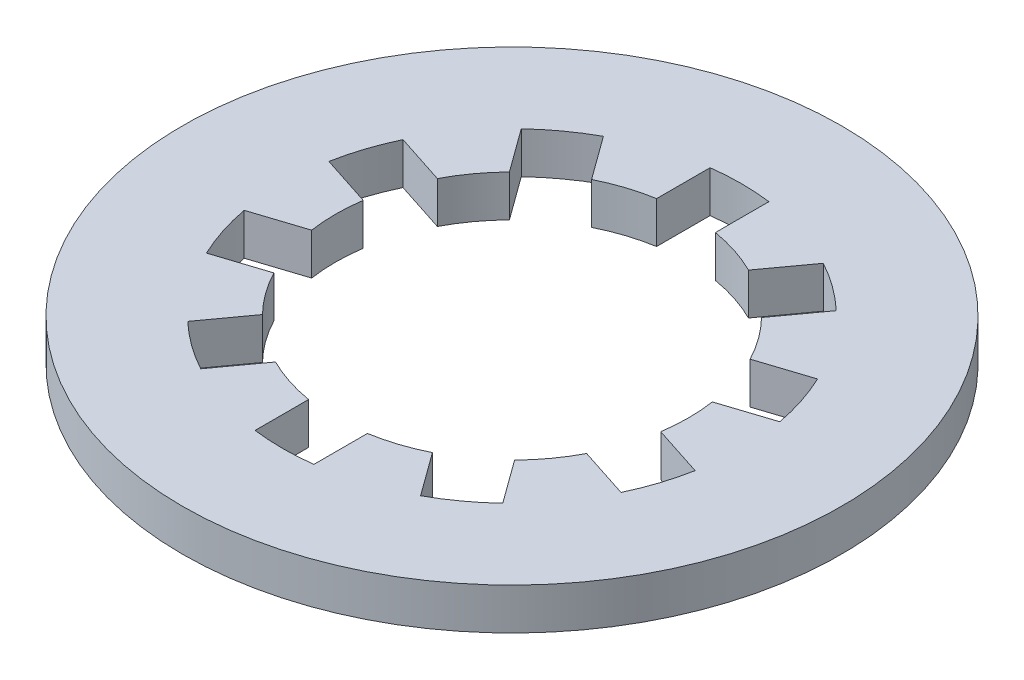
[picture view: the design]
ISO-10303-21;
HEADER;
FILE_DESCRIPTION(('STEP AP214'),'2;1');
FILE_NAME('part.step','',(''),(''),'','','');
FILE_SCHEMA(('AUTOMOTIVE_DESIGN { 1 0 10303 214 1 1 1 1 }'));
ENDSEC;
DATA;
#1=APPLICATION_CONTEXT('core data for automotive mechanical design processes');
#2=APPLICATION_PROTOCOL_DEFINITION('international standard','automotive_design',2000,#1);
#3=PRODUCT_CONTEXT('',#1,'mechanical');
#4=PRODUCT('Part','Part','',(#3));
#5=PRODUCT_RELATED_PRODUCT_CATEGORY('part','',(#4));
#6=PRODUCT_DEFINITION_FORMATION('','',#4);
#7=PRODUCT_DEFINITION_CONTEXT('part definition',#1,'design');
#8=PRODUCT_DEFINITION('design','',#6,#7);
#9=PRODUCT_DEFINITION_SHAPE('','',#8);
#10=(LENGTH_UNIT() NAMED_UNIT(*) SI_UNIT(.MILLI.,.METRE.));
#11=(NAMED_UNIT(*) PLANE_ANGLE_UNIT() SI_UNIT($,.RADIAN.));
#12=(NAMED_UNIT(*) SI_UNIT($,.STERADIAN.) SOLID_ANGLE_UNIT());
#13=UNCERTAINTY_MEASURE_WITH_UNIT(LENGTH_MEASURE(1.E-05),#10,'distance_accuracy_value','');
#14=(GEOMETRIC_REPRESENTATION_CONTEXT(3) GLOBAL_UNCERTAINTY_ASSIGNED_CONTEXT((#13)) GLOBAL_UNIT_ASSIGNED_CONTEXT((#10,
#11,#12)) REPRESENTATION_CONTEXT('',''));
#15=CARTESIAN_POINT('',(0.,0.,0.));
#16=DIRECTION('',(0.,0.,1.));
#17=DIRECTION('',(1.,0.,0.));
#18=AXIS2_PLACEMENT_3D('',#15,#16,#17);
#19=CARTESIAN_POINT('',(0.,0.6096,0.));
#20=DIRECTION('',(0.,-1.,0.));
#21=DIRECTION('',(0.,0.,-1.));
#22=AXIS2_PLACEMENT_3D('',#19,#20,#21);
#23=CYLINDRICAL_SURFACE('',#22,2.5908);
#24=DIRECTION('',(0.,1.,0.));
#25=VECTOR('',#24,1.);
#26=CARTESIAN_POINT('',(-1.15220106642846,0.,2.32049075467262));
#27=LINE('',#26,#25);
#28=CARTESIAN_POINT('',(-1.15220106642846,0.,2.32049075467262));
#29=VERTEX_POINT('',#28);
#30=CARTESIAN_POINT('',(-1.15220106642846,0.6096,2.32049075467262));
#31=VERTEX_POINT('',#30);
#32=EDGE_CURVE('E565',#29,#31,#27,.T.);
#33=ORIENTED_EDGE('',*,*,#32,.T.);
#34=CARTESIAN_POINT('',(0.,0.6096,0.));
#35=DIRECTION('',(0.,1.,0.));
#36=DIRECTION('',(0.,0.,1.));
#37=AXIS2_PLACEMENT_3D('',#34,#35,#36);
#38=CIRCLE('',#37,2.5908);
#39=CARTESIAN_POINT('',(-0.4318,0.6096,2.55456325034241));
#40=VERTEX_POINT('',#39);
#41=EDGE_CURVE('E332',#31,#40,#38,.T.);
#42=ORIENTED_EDGE('',*,*,#41,.T.);
#43=DIRECTION('',(0.,1.,0.));
#44=VECTOR('',#43,1.);
#45=CARTESIAN_POINT('',(-0.4318,0.,2.55456325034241));
#46=LINE('',#45,#44);
#47=CARTESIAN_POINT('',(-0.4318,0.,2.55456325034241));
#48=VERTEX_POINT('',#47);
#49=EDGE_CURVE('E340',#48,#40,#46,.T.);
#50=ORIENTED_EDGE('',*,*,#49,.F.);
#51=CARTESIAN_POINT('',(0.,0.,0.));
#52=DIRECTION('',(0.,1.,0.));
#53=DIRECTION('',(0.,0.,1.));
#54=AXIS2_PLACEMENT_3D('',#51,#52,#53);
#55=CIRCLE('',#54,2.5908);
#56=EDGE_CURVE('E322',#29,#48,#55,.T.);
#57=ORIENTED_EDGE('',*,*,#56,.F.);
#58=EDGE_LOOP('',(#33,#42,#50,#57));
#59=FACE_BOUND('',#58,.T.);
#60=ADVANCED_FACE('F41',(#59),#23,.F.);
#61=DIRECTION('',(0.,1.,0.));
#62=VECTOR('',#61,1.);
#63=CARTESIAN_POINT('',(-1.85086814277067,0.,1.81287941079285));
#64=LINE('',#63,#62);
#65=CARTESIAN_POINT('',(-1.85086814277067,0.,1.81287941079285));
#66=VERTEX_POINT('',#65);
#67=CARTESIAN_POINT('',(-1.85086814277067,0.6096,1.81287941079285));
#68=VERTEX_POINT('',#67);
#69=EDGE_CURVE('E301',#66,#68,#64,.T.);
#70=ORIENTED_EDGE('',*,*,#69,.F.);
#71=CARTESIAN_POINT('',(-2.29610048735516,0.,1.20006966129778));
#72=VERTEX_POINT('',#71);
#73=EDGE_CURVE('E312',#72,#66,#55,.T.);
#74=ORIENTED_EDGE('',*,*,#73,.F.);
#75=DIRECTION('',(0.,1.,0.));
#76=VECTOR('',#75,1.);
#77=CARTESIAN_POINT('',(-2.29610048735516,0.,1.20006966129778));
#78=LINE('',#77,#76);
#79=CARTESIAN_POINT('',(-2.29610048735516,0.6096,1.20006966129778));
#80=VERTEX_POINT('',#79);
#81=EDGE_CURVE('E537',#72,#80,#78,.T.);
#82=ORIENTED_EDGE('',*,*,#81,.T.);
#83=EDGE_CURVE('E314',#80,#68,#38,.T.);
#84=ORIENTED_EDGE('',*,*,#83,.T.);
#85=EDGE_LOOP('',(#70,#74,#82,#84));
#86=FACE_BOUND('',#85,.T.);
#87=ADVANCED_FACE('F311',(#86),#23,.F.);
#88=DIRECTION('',(0.,1.,0.));
#89=VECTOR('',#88,1.);
#90=CARTESIAN_POINT('',(-2.56296756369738,0.,0.378737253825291));
#91=LINE('',#90,#89);
#92=CARTESIAN_POINT('',(-2.56296756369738,0.,0.378737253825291));
#93=VERTEX_POINT('',#92);
#94=CARTESIAN_POINT('',(-2.56296756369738,0.6096,0.378737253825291));
#95=VERTEX_POINT('',#94);
#96=EDGE_CURVE('E547',#93,#95,#91,.T.);
#97=ORIENTED_EDGE('',*,*,#96,.F.);
#98=CARTESIAN_POINT('',(-2.56296756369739,0.,-0.378737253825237));
#99=VERTEX_POINT('',#98);
#100=EDGE_CURVE('E325',#99,#93,#55,.T.);
#101=ORIENTED_EDGE('',*,*,#100,.F.);
#102=DIRECTION('',(0.,1.,0.));
#103=VECTOR('',#102,1.);
#104=CARTESIAN_POINT('',(-2.56296756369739,0.,-0.378737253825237));
#105=LINE('',#104,#103);
#106=CARTESIAN_POINT('',(-2.56296756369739,0.6096,-0.378737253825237));
#107=VERTEX_POINT('',#106);
#108=EDGE_CURVE('E515',#99,#107,#105,.T.);
#109=ORIENTED_EDGE('',*,*,#108,.T.);
#110=EDGE_CURVE('E662',#107,#95,#38,.T.);
#111=ORIENTED_EDGE('',*,*,#110,.T.);
#112=EDGE_LOOP('',(#97,#101,#109,#111));
#113=FACE_BOUND('',#112,.T.);
#114=ADVANCED_FACE('F656',(#113),#23,.F.);
#115=DIRECTION('',(0.,1.,0.));
#116=VECTOR('',#115,1.);
#117=CARTESIAN_POINT('',(-2.29610048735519,0.,-1.20006966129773));
#118=LINE('',#117,#116);
#119=CARTESIAN_POINT('',(-2.29610048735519,0.,-1.20006966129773));
#120=VERTEX_POINT('',#119);
#121=CARTESIAN_POINT('',(-2.29610048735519,0.6096,-1.20006966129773));
#122=VERTEX_POINT('',#121);
#123=EDGE_CURVE('E519',#120,#122,#118,.T.);
#124=ORIENTED_EDGE('',*,*,#123,.F.);
#125=CARTESIAN_POINT('',(-1.85086814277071,0.,-1.81287941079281));
#126=VERTEX_POINT('',#125);
#127=EDGE_CURVE('E328',#126,#120,#55,.T.);
#128=ORIENTED_EDGE('',*,*,#127,.F.);
#129=DIRECTION('',(0.,1.,0.));
#130=VECTOR('',#129,1.);
#131=CARTESIAN_POINT('',(-1.85086814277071,0.,-1.81287941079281));
#132=LINE('',#131,#130);
#133=CARTESIAN_POINT('',(-1.85086814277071,0.6096,-1.81287941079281));
#134=VERTEX_POINT('',#133);
#135=EDGE_CURVE('E488',#126,#134,#132,.T.);
#136=ORIENTED_EDGE('',*,*,#135,.T.);
#137=EDGE_CURVE('E644',#134,#122,#38,.T.);
#138=ORIENTED_EDGE('',*,*,#137,.T.);
#139=EDGE_LOOP('',(#124,#128,#136,#138));
#140=FACE_BOUND('',#139,.T.);
#141=ADVANCED_FACE('F639',(#140),#23,.F.);
#142=DIRECTION('',(0.,1.,0.));
#143=VECTOR('',#142,1.);
#144=CARTESIAN_POINT('',(-1.15220106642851,0.,-2.3204907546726));
#145=LINE('',#144,#143);
#146=CARTESIAN_POINT('',(-1.15220106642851,0.,-2.3204907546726));
#147=VERTEX_POINT('',#146);
#148=CARTESIAN_POINT('',(-1.15220106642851,0.6096,-2.3204907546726));
#149=VERTEX_POINT('',#148);
#150=EDGE_CURVE('E494',#147,#149,#145,.T.);
#151=ORIENTED_EDGE('',*,*,#150,.F.);
#152=CARTESIAN_POINT('',(-0.431800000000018,0.,-2.55456325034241));
#153=VERTEX_POINT('',#152);
#154=EDGE_CURVE('E631',#153,#147,#55,.T.);
#155=ORIENTED_EDGE('',*,*,#154,.F.);
#156=DIRECTION('',(0.,1.,0.));
#157=VECTOR('',#156,1.);
#158=CARTESIAN_POINT('',(-0.431800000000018,0.,-2.55456325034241));
#159=LINE('',#158,#157);
#160=CARTESIAN_POINT('',(-0.431800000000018,0.6096,-2.55456325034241));
#161=VERTEX_POINT('',#160);
#162=EDGE_CURVE('E459',#153,#161,#159,.T.);
#163=ORIENTED_EDGE('',*,*,#162,.T.);
#164=EDGE_CURVE('E673',#161,#149,#38,.T.);
#165=ORIENTED_EDGE('',*,*,#164,.T.);
#166=EDGE_LOOP('',(#151,#155,#163,#165));
#167=FACE_BOUND('',#166,.T.);
#168=ADVANCED_FACE('F736',(#167),#23,.F.);
#169=DIRECTION('',(0.,1.,0.));
#170=VECTOR('',#169,1.);
#171=CARTESIAN_POINT('',(0.431799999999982,0.,-2.55456325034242));
#172=LINE('',#171,#170);
#173=CARTESIAN_POINT('',(0.431799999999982,0.,-2.55456325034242));
#174=VERTEX_POINT('',#173);
#175=CARTESIAN_POINT('',(0.431799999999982,0.6096,-2.55456325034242));
#176=VERTEX_POINT('',#175);
#177=EDGE_CURVE('E466',#174,#176,#172,.T.);
#178=ORIENTED_EDGE('',*,*,#177,.F.);
#179=CARTESIAN_POINT('',(1.15220106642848,0.,-2.32049075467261));
#180=VERTEX_POINT('',#179);
#181=EDGE_CURVE('E628',#180,#174,#55,.T.);
#182=ORIENTED_EDGE('',*,*,#181,.F.);
#183=DIRECTION('',(0.,1.,0.));
#184=VECTOR('',#183,1.);
#185=CARTESIAN_POINT('',(1.15220106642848,0.,-2.32049075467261));
#186=LINE('',#185,#184);
#187=CARTESIAN_POINT('',(1.15220106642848,0.6096,-2.32049075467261));
#188=VERTEX_POINT('',#187);
#189=EDGE_CURVE('E432',#180,#188,#186,.T.);
#190=ORIENTED_EDGE('',*,*,#189,.T.);
#191=EDGE_CURVE('E671',#188,#176,#38,.T.);
#192=ORIENTED_EDGE('',*,*,#191,.T.);
#193=EDGE_LOOP('',(#178,#182,#190,#192));
#194=FACE_BOUND('',#193,.T.);
#195=ADVANCED_FACE('F727',(#194),#23,.F.);
#196=DIRECTION('',(0.,1.,0.));
#197=VECTOR('',#196,1.);
#198=CARTESIAN_POINT('',(1.85086814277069,0.,-1.81287941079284));
#199=LINE('',#198,#197);
#200=CARTESIAN_POINT('',(1.85086814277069,0.,-1.81287941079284));
#201=VERTEX_POINT('',#200);
#202=CARTESIAN_POINT('',(1.85086814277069,0.6096,-1.81287941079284));
#203=VERTEX_POINT('',#202);
#204=EDGE_CURVE('E445',#201,#203,#199,.T.);
#205=ORIENTED_EDGE('',*,*,#204,.F.);
#206=CARTESIAN_POINT('',(2.29610048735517,0.,-1.20006966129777));
#207=VERTEX_POINT('',#206);
#208=EDGE_CURVE('E622',#207,#201,#55,.T.);
#209=ORIENTED_EDGE('',*,*,#208,.F.);
#210=DIRECTION('',(0.,1.,0.));
#211=VECTOR('',#210,1.);
#212=CARTESIAN_POINT('',(2.29610048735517,0.,-1.20006966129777));
#213=LINE('',#212,#211);
#214=CARTESIAN_POINT('',(2.29610048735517,0.6096,-1.20006966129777));
#215=VERTEX_POINT('',#214);
#216=EDGE_CURVE('E407',#207,#215,#213,.T.);
#217=ORIENTED_EDGE('',*,*,#216,.T.);
#218=EDGE_CURVE('E679',#215,#203,#38,.T.);
#219=ORIENTED_EDGE('',*,*,#218,.T.);
#220=EDGE_LOOP('',(#205,#209,#217,#219));
#221=FACE_BOUND('',#220,.T.);
#222=ADVANCED_FACE('F713',(#221),#23,.F.);
#223=DIRECTION('',(0.,1.,0.));
#224=VECTOR('',#223,1.);
#225=CARTESIAN_POINT('',(2.56296756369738,0.,-0.378737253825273));
#226=LINE('',#225,#224);
#227=CARTESIAN_POINT('',(2.56296756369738,0.,-0.378737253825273));
#228=VERTEX_POINT('',#227);
#229=CARTESIAN_POINT('',(2.56296756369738,0.6096,-0.378737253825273));
#230=VERTEX_POINT('',#229);
#231=EDGE_CURVE('E417',#228,#230,#226,.T.);
#232=ORIENTED_EDGE('',*,*,#231,.F.);
#233=CARTESIAN_POINT('',(2.56296756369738,0.,0.378737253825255));
#234=VERTEX_POINT('',#233);
#235=EDGE_CURVE('E621',#234,#228,#55,.T.);
#236=ORIENTED_EDGE('',*,*,#235,.F.);
#237=DIRECTION('',(0.,1.,0.));
#238=VECTOR('',#237,1.);
#239=CARTESIAN_POINT('',(2.56296756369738,0.,0.378737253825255));
#240=LINE('',#239,#238);
#241=CARTESIAN_POINT('',(2.56296756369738,0.6096,0.378737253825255));
#242=VERTEX_POINT('',#241);
#243=EDGE_CURVE('E385',#234,#242,#240,.T.);
#244=ORIENTED_EDGE('',*,*,#243,.T.);
#245=EDGE_CURVE('E681',#242,#230,#38,.T.);
#246=ORIENTED_EDGE('',*,*,#245,.T.);
#247=EDGE_LOOP('',(#232,#236,#244,#246));
#248=FACE_BOUND('',#247,.T.);
#249=ADVANCED_FACE('F705',(#248),#23,.F.);
#250=DIRECTION('',(0.,1.,0.));
#251=VECTOR('',#250,1.);
#252=CARTESIAN_POINT('',(2.29610048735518,0.,1.20006966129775));
#253=LINE('',#252,#251);
#254=CARTESIAN_POINT('',(2.29610048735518,0.,1.20006966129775));
#255=VERTEX_POINT('',#254);
#256=CARTESIAN_POINT('',(2.29610048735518,0.6096,1.20006966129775));
#257=VERTEX_POINT('',#256);
#258=EDGE_CURVE('E389',#255,#257,#253,.T.);
#259=ORIENTED_EDGE('',*,*,#258,.F.);
#260=CARTESIAN_POINT('',(1.8508681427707,0.,1.81287941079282));
#261=VERTEX_POINT('',#260);
#262=EDGE_CURVE('E335',#261,#255,#55,.T.);
#263=ORIENTED_EDGE('',*,*,#262,.F.);
#264=DIRECTION('',(0.,1.,0.));
#265=VECTOR('',#264,1.);
#266=CARTESIAN_POINT('',(1.8508681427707,0.,1.81287941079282));
#267=LINE('',#266,#265);
#268=CARTESIAN_POINT('',(1.8508681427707,0.6096,1.81287941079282));
#269=VERTEX_POINT('',#268);
#270=EDGE_CURVE('E358',#261,#269,#267,.T.);
#271=ORIENTED_EDGE('',*,*,#270,.T.);
#272=EDGE_CURVE('E337',#269,#257,#38,.T.);
#273=ORIENTED_EDGE('',*,*,#272,.T.);
#274=EDGE_LOOP('',(#259,#263,#271,#273));
#275=FACE_BOUND('',#274,.T.);
#276=ADVANCED_FACE('F623',(#275),#23,.F.);
#277=CARTESIAN_POINT('',(0.,0.6096,0.));
#278=DIRECTION('',(0.,1.,0.));
#279=DIRECTION('',(0.,0.,1.));
#280=AXIS2_PLACEMENT_3D('',#277,#278,#279);
#281=PLANE('',#280);
#282=DIRECTION('',(0.587785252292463,0.,-0.809016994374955));
#283=VECTOR('',#282,1.);
#284=CARTESIAN_POINT('',(-1.61401369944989,0.6096,2.95612131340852));
#285=LINE('',#284,#283);
#286=CARTESIAN_POINT('',(-1.61401369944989,0.6096,2.95612131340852));
#287=VERTEX_POINT('',#286);
#288=EDGE_CURVE('E306',#287,#31,#285,.T.);
#289=ORIENTED_EDGE('',*,*,#288,.F.);
#290=CARTESIAN_POINT('',(0.,0.6096,0.));
#291=DIRECTION('',(0.,1.,0.));
#292=DIRECTION('',(-0.587785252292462,0.,0.809016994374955));
#293=AXIS2_PLACEMENT_3D('',#290,#291,#292);
#294=CIRCLE('',#293,3.36804);
#295=CARTESIAN_POINT('',(-2.3126807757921,0.6096,2.44850996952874));
#296=VERTEX_POINT('',#295);
#297=EDGE_CURVE('E572',#296,#287,#294,.T.);
#298=ORIENTED_EDGE('',*,*,#297,.F.);
#299=DIRECTION('',(-0.587785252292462,0.,0.809016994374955));
#300=VECTOR('',#299,1.);
#301=CARTESIAN_POINT('',(-2.3126807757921,0.6096,2.44850996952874));
#302=LINE('',#301,#300);
#303=EDGE_CURVE('E577',#68,#296,#302,.T.);
#304=ORIENTED_EDGE('',*,*,#303,.F.);
#305=ORIENTED_EDGE('',*,*,#83,.F.);
#306=DIRECTION('',(0.95105651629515,0.,-0.309016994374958));
#307=VECTOR('',#306,1.);
#308=CARTESIAN_POINT('',(-3.04332902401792,0.6096,1.44285893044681));
#309=LINE('',#308,#307);
#310=CARTESIAN_POINT('',(-3.04332902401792,0.6096,1.44285893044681));
#311=VERTEX_POINT('',#310);
#312=EDGE_CURVE('E551',#311,#80,#309,.T.);
#313=ORIENTED_EDGE('',*,*,#312,.F.);
#314=CARTESIAN_POINT('',(0.,0.6096,0.));
#315=DIRECTION('',(0.,1.,0.));
#316=DIRECTION('',(-0.95105651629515,0.,0.309016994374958));
#317=AXIS2_PLACEMENT_3D('',#314,#315,#316);
#318=CIRCLE('',#317,3.36804);
#319=CARTESIAN_POINT('',(-3.31019610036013,0.6096,0.621526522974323));
#320=VERTEX_POINT('',#319);
#321=EDGE_CURVE('E558',#320,#311,#318,.T.);
#322=ORIENTED_EDGE('',*,*,#321,.F.);
#323=DIRECTION('',(-0.95105651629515,0.,0.309016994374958));
#324=VECTOR('',#323,1.);
#325=CARTESIAN_POINT('',(-3.31019610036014,0.6096,0.621526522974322));
#326=LINE('',#325,#324);
#327=EDGE_CURVE('E559',#95,#320,#326,.T.);
#328=ORIENTED_EDGE('',*,*,#327,.F.);
#329=ORIENTED_EDGE('',*,*,#110,.F.);
#330=DIRECTION('',(0.951056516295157,0.,0.309016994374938));
#331=VECTOR('',#330,1.);
#332=CARTESIAN_POINT('',(-3.31019610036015,0.6096,-0.621526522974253));
#333=LINE('',#332,#331);
#334=CARTESIAN_POINT('',(-3.31019610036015,0.6096,-0.621526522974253));
#335=VERTEX_POINT('',#334);
#336=EDGE_CURVE('E526',#335,#107,#333,.T.);
#337=ORIENTED_EDGE('',*,*,#336,.F.);
#338=CARTESIAN_POINT('',(0.,0.6096,0.));
#339=DIRECTION('',(0.,1.,0.));
#340=DIRECTION('',(-0.951056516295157,0.,-0.309016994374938));
#341=AXIS2_PLACEMENT_3D('',#338,#339,#340);
#342=CIRCLE('',#341,3.36804);
#343=CARTESIAN_POINT('',(-3.04332902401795,0.6096,-1.44285893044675));
#344=VERTEX_POINT('',#343);
#345=EDGE_CURVE('E535',#344,#335,#342,.T.);
#346=ORIENTED_EDGE('',*,*,#345,.F.);
#347=DIRECTION('',(-0.951056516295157,0.,-0.309016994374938));
#348=VECTOR('',#347,1.);
#349=CARTESIAN_POINT('',(-3.04332902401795,0.6096,-1.44285893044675));
#350=LINE('',#349,#348);
#351=EDGE_CURVE('E533',#122,#344,#350,.T.);
#352=ORIENTED_EDGE('',*,*,#351,.F.);
#353=ORIENTED_EDGE('',*,*,#137,.F.);
#354=DIRECTION('',(0.58778525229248,0.,0.809016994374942));
#355=VECTOR('',#354,1.);
#356=CARTESIAN_POINT('',(-2.31268077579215,0.6096,-2.44850996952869));
#357=LINE('',#356,#355);
#358=CARTESIAN_POINT('',(-2.31268077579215,0.6096,-2.44850996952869));
#359=VERTEX_POINT('',#358);
#360=EDGE_CURVE('E503',#359,#134,#357,.T.);
#361=ORIENTED_EDGE('',*,*,#360,.F.);
#362=CARTESIAN_POINT('',(0.,0.6096,0.));
#363=DIRECTION('',(0.,1.,0.));
#364=DIRECTION('',(-0.58778525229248,0.,-0.809016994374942));
#365=AXIS2_PLACEMENT_3D('',#362,#363,#364);
#366=CIRCLE('',#365,3.36804);
#367=CARTESIAN_POINT('',(-1.61401369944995,0.6096,-2.95612131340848));
#368=VERTEX_POINT('',#367);
#369=EDGE_CURVE('E506',#368,#359,#366,.T.);
#370=ORIENTED_EDGE('',*,*,#369,.F.);
#371=DIRECTION('',(-0.58778525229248,0.,-0.809016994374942));
#372=VECTOR('',#371,1.);
#373=CARTESIAN_POINT('',(-1.61401369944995,0.6096,-2.95612131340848));
#374=LINE('',#373,#372);
#375=EDGE_CURVE('E508',#149,#368,#374,.T.);
#376=ORIENTED_EDGE('',*,*,#375,.F.);
#377=ORIENTED_EDGE('',*,*,#164,.F.);
#378=DIRECTION('',(0.,0.,1.));
#379=VECTOR('',#378,1.);
#380=CARTESIAN_POINT('',(-0.431800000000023,0.6096,-3.34024582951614));
#381=LINE('',#380,#379);
#382=CARTESIAN_POINT('',(-0.431800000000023,0.6096,-3.34024582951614));
#383=VERTEX_POINT('',#382);
#384=EDGE_CURVE('E480',#383,#161,#381,.T.);
#385=ORIENTED_EDGE('',*,*,#384,.F.);
#386=CARTESIAN_POINT('',(0.,0.6096,0.));
#387=DIRECTION('',(0.,1.,0.));
#388=DIRECTION('',(0.,0.,-1.));
#389=AXIS2_PLACEMENT_3D('',#386,#387,#388);
#390=CIRCLE('',#389,3.36804);
#391=CARTESIAN_POINT('',(0.431799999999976,0.6096,-3.34024582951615));
#392=VERTEX_POINT('',#391);
#393=EDGE_CURVE('E479',#392,#383,#390,.T.);
#394=ORIENTED_EDGE('',*,*,#393,.F.);
#395=DIRECTION('',(0.,0.,-1.));
#396=VECTOR('',#395,1.);
#397=CARTESIAN_POINT('',(0.431799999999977,0.6096,-3.34024582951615));
#398=LINE('',#397,#396);
#399=EDGE_CURVE('E484',#176,#392,#398,.T.);
#400=ORIENTED_EDGE('',*,*,#399,.F.);
#401=ORIENTED_EDGE('',*,*,#191,.F.);
#402=DIRECTION('',(-0.587785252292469,0.,0.809016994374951));
#403=VECTOR('',#402,1.);
#404=CARTESIAN_POINT('',(1.61401369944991,0.6096,-2.9561213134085));
#405=LINE('',#404,#403);
#406=CARTESIAN_POINT('',(1.61401369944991,0.6096,-2.9561213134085));
#407=VERTEX_POINT('',#406);
#408=EDGE_CURVE('E451',#407,#188,#405,.T.);
#409=ORIENTED_EDGE('',*,*,#408,.F.);
#410=CARTESIAN_POINT('',(0.,0.6096,0.));
#411=DIRECTION('',(0.,1.,0.));
#412=DIRECTION('',(0.587785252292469,0.,-0.809016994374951));
#413=AXIS2_PLACEMENT_3D('',#410,#411,#412);
#414=CIRCLE('',#413,3.36804);
#415=CARTESIAN_POINT('',(2.31268077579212,0.6096,-2.44850996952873));
#416=VERTEX_POINT('',#415);
#417=EDGE_CURVE('E453',#416,#407,#414,.T.);
#418=ORIENTED_EDGE('',*,*,#417,.F.);
#419=DIRECTION('',(0.587785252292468,0.,-0.809016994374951));
#420=VECTOR('',#419,1.);
#421=CARTESIAN_POINT('',(2.31268077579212,0.6096,-2.44850996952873));
#422=LINE('',#421,#420);
#423=EDGE_CURVE('E460',#203,#416,#422,.T.);
#424=ORIENTED_EDGE('',*,*,#423,.F.);
#425=ORIENTED_EDGE('',*,*,#218,.F.);
#426=DIRECTION('',(-0.951056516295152,0.,0.309016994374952));
#427=VECTOR('',#426,1.);
#428=CARTESIAN_POINT('',(3.04332902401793,0.6096,-1.44285893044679));
#429=LINE('',#428,#427);
#430=CARTESIAN_POINT('',(3.04332902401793,0.6096,-1.44285893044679));
#431=VERTEX_POINT('',#430);
#432=EDGE_CURVE('E424',#431,#215,#429,.T.);
#433=ORIENTED_EDGE('',*,*,#432,.F.);
#434=CARTESIAN_POINT('',(0.,0.6096,0.));
#435=DIRECTION('',(0.,1.,0.));
#436=DIRECTION('',(0.951056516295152,0.,-0.309016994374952));
#437=AXIS2_PLACEMENT_3D('',#434,#435,#436);
#438=CIRCLE('',#437,3.36804);
#439=CARTESIAN_POINT('',(3.31019610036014,0.6096,-0.6215265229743));
#440=VERTEX_POINT('',#439);
#441=EDGE_CURVE('E426',#440,#431,#438,.T.);
#442=ORIENTED_EDGE('',*,*,#441,.F.);
#443=DIRECTION('',(0.951056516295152,0.,-0.309016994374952));
#444=VECTOR('',#443,1.);
#445=CARTESIAN_POINT('',(3.31019610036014,0.6096,-0.6215265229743));
#446=LINE('',#445,#444);
#447=EDGE_CURVE('E431',#230,#440,#446,.T.);
#448=ORIENTED_EDGE('',*,*,#447,.F.);
#449=ORIENTED_EDGE('',*,*,#245,.F.);
#450=DIRECTION('',(-0.951056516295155,0.,-0.309016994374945));
#451=VECTOR('',#450,1.);
#452=CARTESIAN_POINT('',(3.31019610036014,0.6096,0.621526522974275));
#453=LINE('',#452,#451);
#454=CARTESIAN_POINT('',(3.31019610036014,0.6096,0.621526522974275));
#455=VERTEX_POINT('',#454);
#456=EDGE_CURVE('E396',#455,#242,#453,.T.);
#457=ORIENTED_EDGE('',*,*,#456,.F.);
#458=CARTESIAN_POINT('',(0.,0.6096,0.));
#459=DIRECTION('',(0.,1.,0.));
#460=DIRECTION('',(0.951056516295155,0.,0.309016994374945));
#461=AXIS2_PLACEMENT_3D('',#458,#459,#460);
#462=CIRCLE('',#461,3.36804);
#463=CARTESIAN_POINT('',(3.04332902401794,0.6096,1.44285893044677));
#464=VERTEX_POINT('',#463);
#465=EDGE_CURVE('E405',#464,#455,#462,.T.);
#466=ORIENTED_EDGE('',*,*,#465,.F.);
#467=DIRECTION('',(0.951056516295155,0.,0.309016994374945));
#468=VECTOR('',#467,1.);
#469=CARTESIAN_POINT('',(3.04332902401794,0.6096,1.44285893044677));
#470=LINE('',#469,#468);
#471=EDGE_CURVE('E403',#257,#464,#470,.T.);
#472=ORIENTED_EDGE('',*,*,#471,.F.);
#473=ORIENTED_EDGE('',*,*,#272,.F.);
#474=DIRECTION('',(-0.587785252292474,0.,-0.809016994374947));
#475=VECTOR('',#474,1.);
#476=CARTESIAN_POINT('',(2.31268077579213,0.6096,2.44850996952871));
#477=LINE('',#476,#475);
#478=CARTESIAN_POINT('',(2.31268077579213,0.6096,2.44850996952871));
#479=VERTEX_POINT('',#478);
#480=EDGE_CURVE('E373',#479,#269,#477,.T.);
#481=ORIENTED_EDGE('',*,*,#480,.F.);
#482=CARTESIAN_POINT('',(0.,0.6096,0.));
#483=DIRECTION('',(0.,1.,0.));
#484=DIRECTION('',(0.587785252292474,0.,0.809016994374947));
#485=AXIS2_PLACEMENT_3D('',#482,#483,#484);
#486=CIRCLE('',#485,3.36804);
#487=CARTESIAN_POINT('',(1.61401369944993,0.6096,2.95612131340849));
#488=VERTEX_POINT('',#487);
#489=EDGE_CURVE('E376',#488,#479,#486,.T.);
#490=ORIENTED_EDGE('',*,*,#489,.F.);
#491=DIRECTION('',(0.587785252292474,0.,0.809016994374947));
#492=VECTOR('',#491,1.);
#493=CARTESIAN_POINT('',(1.61401369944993,0.6096,2.95612131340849));
#494=LINE('',#493,#492);
#495=CARTESIAN_POINT('',(1.1522010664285,0.6096,2.32049075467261));
#496=VERTEX_POINT('',#495);
#497=EDGE_CURVE('E378',#496,#488,#494,.T.);
#498=ORIENTED_EDGE('',*,*,#497,.F.);
#499=CARTESIAN_POINT('',(0.4318,0.6096,2.55456325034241));
#500=VERTEX_POINT('',#499);
#501=EDGE_CURVE('E334',#500,#496,#38,.T.);
#502=ORIENTED_EDGE('',*,*,#501,.F.);
#503=DIRECTION('',(0.,0.,-1.));
#504=VECTOR('',#503,1.);
#505=CARTESIAN_POINT('',(0.4318,0.6096,3.34024582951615));
#506=LINE('',#505,#504);
#507=CARTESIAN_POINT('',(0.4318,0.6096,3.34024582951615));
#508=VERTEX_POINT('',#507);
#509=EDGE_CURVE('E350',#508,#500,#506,.T.);
#510=ORIENTED_EDGE('',*,*,#509,.F.);
#511=CARTESIAN_POINT('',(0.,0.6096,0.));
#512=DIRECTION('',(0.,1.,0.));
#513=DIRECTION('',(0.,0.,1.));
#514=AXIS2_PLACEMENT_3D('',#511,#512,#513);
#515=CIRCLE('',#514,3.36804);
#516=CARTESIAN_POINT('',(-0.431799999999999,0.6096,3.34024582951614));
#517=VERTEX_POINT('',#516);
#518=EDGE_CURVE('E349',#517,#508,#515,.T.);
#519=ORIENTED_EDGE('',*,*,#518,.F.);
#520=DIRECTION('',(0.,0.,1.));
#521=VECTOR('',#520,1.);
#522=CARTESIAN_POINT('',(-0.4318,0.6096,3.34024582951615));
#523=LINE('',#522,#521);
#524=EDGE_CURVE('E354',#40,#517,#523,.T.);
#525=ORIENTED_EDGE('',*,*,#524,.F.);
#526=ORIENTED_EDGE('',*,*,#41,.F.);
#527=EDGE_LOOP('',(#289,#298,#304,#305,#313,#322,#328,#329,#337,#346,#352,#353,#361,#370,#376,
#377,#385,#394,#400,#401,#409,#418,#424,#425,#433,#442,#448,#449,#457,#466,#472,#473,#481,#490,
#498,#502,#510,#519,#525,#526));
#528=FACE_BOUND('',#527,.T.);
#529=CARTESIAN_POINT('',(0.,0.6096,0.));
#530=DIRECTION('',(0.,1.,0.));
#531=DIRECTION('',(0.,0.,1.));
#532=AXIS2_PLACEMENT_3D('',#529,#530,#531);
#533=CIRCLE('',#532,4.8387);
#534=CARTESIAN_POINT('',(0.,0.6096,4.8387));
#535=VERTEX_POINT('',#534);
#536=EDGE_CURVE('E11',#535,#535,#533,.T.);
#537=ORIENTED_EDGE('',*,*,#536,.T.);
#538=EDGE_LOOP('',(#537));
#539=FACE_BOUND('',#538,.T.);
#540=ADVANCED_FACE('F594',(#528,#539),#281,.T.);
#541=CARTESIAN_POINT('',(0.,0.,0.));
#542=DIRECTION('',(0.,1.,0.));
#543=DIRECTION('',(0.,0.,1.));
#544=AXIS2_PLACEMENT_3D('',#541,#542,#543);
#545=PLANE('',#544);
#546=CARTESIAN_POINT('',(0.,0.,0.));
#547=DIRECTION('',(0.,1.,0.));
#548=DIRECTION('',(0.,0.,1.));
#549=AXIS2_PLACEMENT_3D('',#546,#547,#548);
#550=CIRCLE('',#549,4.8387);
#551=CARTESIAN_POINT('',(0.,0.,4.8387));
#552=VERTEX_POINT('',#551);
#553=EDGE_CURVE('E44',#552,#552,#550,.T.);
#554=ORIENTED_EDGE('',*,*,#553,.F.);
#555=EDGE_LOOP('',(#554));
#556=FACE_BOUND('',#555,.T.);
#557=CARTESIAN_POINT('',(0.,0.,0.));
#558=DIRECTION('',(0.,1.,0.));
#559=DIRECTION('',(-0.587785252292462,0.,0.809016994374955));
#560=AXIS2_PLACEMENT_3D('',#557,#558,#559);
#561=CIRCLE('',#560,3.36804);
#562=CARTESIAN_POINT('',(-2.3126807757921,0.,2.44850996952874));
#563=VERTEX_POINT('',#562);
#564=CARTESIAN_POINT('',(-1.61401369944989,0.,2.95612131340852));
#565=VERTEX_POINT('',#564);
#566=EDGE_CURVE('E57',#563,#565,#561,.T.);
#567=ORIENTED_EDGE('',*,*,#566,.T.);
#568=DIRECTION('',(0.587785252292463,0.,-0.809016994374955));
#569=VECTOR('',#568,1.);
#570=CARTESIAN_POINT('',(-1.61401369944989,0.,2.95612131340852));
#571=LINE('',#570,#569);
#572=EDGE_CURVE('E317',#565,#29,#571,.T.);
#573=ORIENTED_EDGE('',*,*,#572,.T.);
#574=ORIENTED_EDGE('',*,*,#56,.T.);
#575=DIRECTION('',(0.,0.,1.));
#576=VECTOR('',#575,1.);
#577=CARTESIAN_POINT('',(-0.4318,0.,3.34024582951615));
#578=LINE('',#577,#576);
#579=CARTESIAN_POINT('',(-0.431799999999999,0.,3.34024582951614));
#580=VERTEX_POINT('',#579);
#581=EDGE_CURVE('E347',#48,#580,#578,.T.);
#582=ORIENTED_EDGE('',*,*,#581,.T.);
#583=CARTESIAN_POINT('',(0.,0.,0.));
#584=DIRECTION('',(0.,1.,0.));
#585=DIRECTION('',(0.,0.,1.));
#586=AXIS2_PLACEMENT_3D('',#583,#584,#585);
#587=CIRCLE('',#586,3.36804);
#588=CARTESIAN_POINT('',(0.4318,0.,3.34024582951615));
#589=VERTEX_POINT('',#588);
#590=EDGE_CURVE('E360',#580,#589,#587,.T.);
#591=ORIENTED_EDGE('',*,*,#590,.T.);
#592=DIRECTION('',(0.,0.,-1.));
#593=VECTOR('',#592,1.);
#594=CARTESIAN_POINT('',(0.4318,0.,3.34024582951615));
#595=LINE('',#594,#593);
#596=CARTESIAN_POINT('',(0.4318,0.,2.55456325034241));
#597=VERTEX_POINT('',#596);
#598=EDGE_CURVE('E341',#589,#597,#595,.T.);
#599=ORIENTED_EDGE('',*,*,#598,.T.);
#600=CARTESIAN_POINT('',(1.1522010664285,0.,2.3204907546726));
#601=VERTEX_POINT('',#600);
#602=EDGE_CURVE('E326',#597,#601,#55,.T.);
#603=ORIENTED_EDGE('',*,*,#602,.T.);
#604=DIRECTION('',(0.587785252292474,0.,0.809016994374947));
#605=VECTOR('',#604,1.);
#606=CARTESIAN_POINT('',(1.61401369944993,0.,2.95612131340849));
#607=LINE('',#606,#605);
#608=CARTESIAN_POINT('',(1.61401369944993,0.,2.95612131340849));
#609=VERTEX_POINT('',#608);
#610=EDGE_CURVE('E374',#601,#609,#607,.T.);
#611=ORIENTED_EDGE('',*,*,#610,.T.);
#612=CARTESIAN_POINT('',(0.,0.,0.));
#613=DIRECTION('',(0.,1.,0.));
#614=DIRECTION('',(0.587785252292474,0.,0.809016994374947));
#615=AXIS2_PLACEMENT_3D('',#612,#613,#614);
#616=CIRCLE('',#615,3.36804);
#617=CARTESIAN_POINT('',(2.31268077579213,0.,2.44850996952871));
#618=VERTEX_POINT('',#617);
#619=EDGE_CURVE('E383',#609,#618,#616,.T.);
#620=ORIENTED_EDGE('',*,*,#619,.T.);
#621=DIRECTION('',(-0.587785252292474,0.,-0.809016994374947));
#622=VECTOR('',#621,1.);
#623=CARTESIAN_POINT('',(2.31268077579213,0.,2.44850996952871));
#624=LINE('',#623,#622);
#625=EDGE_CURVE('E370',#618,#261,#624,.T.);
#626=ORIENTED_EDGE('',*,*,#625,.T.);
#627=ORIENTED_EDGE('',*,*,#262,.T.);
#628=DIRECTION('',(0.951056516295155,0.,0.309016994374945));
#629=VECTOR('',#628,1.);
#630=CARTESIAN_POINT('',(3.04332902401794,0.,1.44285893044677));
#631=LINE('',#630,#629);
#632=CARTESIAN_POINT('',(3.04332902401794,0.,1.44285893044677));
#633=VERTEX_POINT('',#632);
#634=EDGE_CURVE('E402',#255,#633,#631,.T.);
#635=ORIENTED_EDGE('',*,*,#634,.T.);
#636=CARTESIAN_POINT('',(0.,0.,0.));
#637=DIRECTION('',(0.,1.,0.));
#638=DIRECTION('',(0.951056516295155,0.,0.309016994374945));
#639=AXIS2_PLACEMENT_3D('',#636,#637,#638);
#640=CIRCLE('',#639,3.36804);
#641=CARTESIAN_POINT('',(3.31019610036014,0.,0.621526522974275));
#642=VERTEX_POINT('',#641);
#643=EDGE_CURVE('E413',#633,#642,#640,.T.);
#644=ORIENTED_EDGE('',*,*,#643,.T.);
#645=DIRECTION('',(-0.951056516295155,0.,-0.309016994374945));
#646=VECTOR('',#645,1.);
#647=CARTESIAN_POINT('',(3.31019610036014,0.,0.621526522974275));
#648=LINE('',#647,#646);
#649=EDGE_CURVE('E391',#642,#234,#648,.T.);
#650=ORIENTED_EDGE('',*,*,#649,.T.);
#651=ORIENTED_EDGE('',*,*,#235,.T.);
#652=DIRECTION('',(0.951056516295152,0.,-0.309016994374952));
#653=VECTOR('',#652,1.);
#654=CARTESIAN_POINT('',(3.31019610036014,0.,-0.6215265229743));
#655=LINE('',#654,#653);
#656=CARTESIAN_POINT('',(3.31019610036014,0.,-0.621526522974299));
#657=VERTEX_POINT('',#656);
#658=EDGE_CURVE('E430',#228,#657,#655,.T.);
#659=ORIENTED_EDGE('',*,*,#658,.T.);
#660=CARTESIAN_POINT('',(0.,0.,0.));
#661=DIRECTION('',(0.,1.,0.));
#662=DIRECTION('',(0.951056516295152,0.,-0.309016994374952));
#663=AXIS2_PLACEMENT_3D('',#660,#661,#662);
#664=CIRCLE('',#663,3.36804);
#665=CARTESIAN_POINT('',(3.04332902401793,0.,-1.44285893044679));
#666=VERTEX_POINT('',#665);
#667=EDGE_CURVE('E440',#657,#666,#664,.T.);
#668=ORIENTED_EDGE('',*,*,#667,.T.);
#669=DIRECTION('',(-0.951056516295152,0.,0.309016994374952));
#670=VECTOR('',#669,1.);
#671=CARTESIAN_POINT('',(3.04332902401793,0.,-1.44285893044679));
#672=LINE('',#671,#670);
#673=EDGE_CURVE('E416',#666,#207,#672,.T.);
#674=ORIENTED_EDGE('',*,*,#673,.T.);
#675=ORIENTED_EDGE('',*,*,#208,.T.);
#676=DIRECTION('',(0.587785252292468,0.,-0.809016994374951));
#677=VECTOR('',#676,1.);
#678=CARTESIAN_POINT('',(2.31268077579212,0.,-2.44850996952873));
#679=LINE('',#678,#677);
#680=CARTESIAN_POINT('',(2.31268077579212,0.,-2.44850996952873));
#681=VERTEX_POINT('',#680);
#682=EDGE_CURVE('E452',#201,#681,#679,.T.);
#683=ORIENTED_EDGE('',*,*,#682,.T.);
#684=CARTESIAN_POINT('',(0.,0.,0.));
#685=DIRECTION('',(0.,1.,0.));
#686=DIRECTION('',(0.587785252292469,0.,-0.809016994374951));
#687=AXIS2_PLACEMENT_3D('',#684,#685,#686);
#688=CIRCLE('',#687,3.36804);
#689=CARTESIAN_POINT('',(1.61401369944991,0.,-2.9561213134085));
#690=VERTEX_POINT('',#689);
#691=EDGE_CURVE('E464',#681,#690,#688,.T.);
#692=ORIENTED_EDGE('',*,*,#691,.T.);
#693=DIRECTION('',(-0.587785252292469,0.,0.809016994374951));
#694=VECTOR('',#693,1.);
#695=CARTESIAN_POINT('',(1.61401369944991,0.,-2.9561213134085));
#696=LINE('',#695,#694);
#697=EDGE_CURVE('E444',#690,#180,#696,.T.);
#698=ORIENTED_EDGE('',*,*,#697,.T.);
#699=ORIENTED_EDGE('',*,*,#181,.T.);
#700=DIRECTION('',(0.,0.,-1.));
#701=VECTOR('',#700,1.);
#702=CARTESIAN_POINT('',(0.431799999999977,0.,-3.34024582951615));
#703=LINE('',#702,#701);
#704=CARTESIAN_POINT('',(0.431799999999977,0.,-3.34024582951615));
#705=VERTEX_POINT('',#704);
#706=EDGE_CURVE('E477',#174,#705,#703,.T.);
#707=ORIENTED_EDGE('',*,*,#706,.T.);
#708=CARTESIAN_POINT('',(0.,0.,0.));
#709=DIRECTION('',(0.,1.,0.));
#710=DIRECTION('',(0.,0.,-1.));
#711=AXIS2_PLACEMENT_3D('',#708,#709,#710);
#712=CIRCLE('',#711,3.36804);
#713=CARTESIAN_POINT('',(-0.431800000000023,0.,-3.34024582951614));
#714=VERTEX_POINT('',#713);
#715=EDGE_CURVE('E490',#705,#714,#712,.T.);
#716=ORIENTED_EDGE('',*,*,#715,.T.);
#717=DIRECTION('',(0.,0.,1.));
#718=VECTOR('',#717,1.);
#719=CARTESIAN_POINT('',(-0.431800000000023,0.,-3.34024582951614));
#720=LINE('',#719,#718);
#721=EDGE_CURVE('E471',#714,#153,#720,.T.);
#722=ORIENTED_EDGE('',*,*,#721,.T.);
#723=ORIENTED_EDGE('',*,*,#154,.T.);
#724=DIRECTION('',(-0.58778525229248,0.,-0.809016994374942));
#725=VECTOR('',#724,1.);
#726=CARTESIAN_POINT('',(-1.61401369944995,0.,-2.95612131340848));
#727=LINE('',#726,#725);
#728=CARTESIAN_POINT('',(-1.61401369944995,0.,-2.95612131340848));
#729=VERTEX_POINT('',#728);
#730=EDGE_CURVE('E504',#147,#729,#727,.T.);
#731=ORIENTED_EDGE('',*,*,#730,.T.);
#732=CARTESIAN_POINT('',(0.,0.,0.));
#733=DIRECTION('',(0.,1.,0.));
#734=DIRECTION('',(-0.58778525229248,0.,-0.809016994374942));
#735=AXIS2_PLACEMENT_3D('',#732,#733,#734);
#736=CIRCLE('',#735,3.36804);
#737=CARTESIAN_POINT('',(-2.31268077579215,0.,-2.44850996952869));
#738=VERTEX_POINT('',#737);
#739=EDGE_CURVE('E513',#729,#738,#736,.T.);
#740=ORIENTED_EDGE('',*,*,#739,.T.);
#741=DIRECTION('',(0.58778525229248,0.,0.809016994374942));
#742=VECTOR('',#741,1.);
#743=CARTESIAN_POINT('',(-2.31268077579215,0.,-2.44850996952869));
#744=LINE('',#743,#742);
#745=EDGE_CURVE('E500',#738,#126,#744,.T.);
#746=ORIENTED_EDGE('',*,*,#745,.T.);
#747=ORIENTED_EDGE('',*,*,#127,.T.);
#748=DIRECTION('',(-0.951056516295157,0.,-0.309016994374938));
#749=VECTOR('',#748,1.);
#750=CARTESIAN_POINT('',(-3.04332902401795,0.,-1.44285893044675));
#751=LINE('',#750,#749);
#752=CARTESIAN_POINT('',(-3.04332902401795,0.,-1.44285893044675));
#753=VERTEX_POINT('',#752);
#754=EDGE_CURVE('E532',#120,#753,#751,.T.);
#755=ORIENTED_EDGE('',*,*,#754,.T.);
#756=CARTESIAN_POINT('',(0.,0.,0.));
#757=DIRECTION('',(0.,1.,0.));
#758=DIRECTION('',(-0.951056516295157,0.,-0.309016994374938));
#759=AXIS2_PLACEMENT_3D('',#756,#757,#758);
#760=CIRCLE('',#759,3.36804);
#761=CARTESIAN_POINT('',(-3.31019610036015,0.,-0.621526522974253));
#762=VERTEX_POINT('',#761);
#763=EDGE_CURVE('E543',#753,#762,#760,.T.);
#764=ORIENTED_EDGE('',*,*,#763,.T.);
#765=DIRECTION('',(0.951056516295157,0.,0.309016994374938));
#766=VECTOR('',#765,1.);
#767=CARTESIAN_POINT('',(-3.31019610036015,0.,-0.621526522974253));
#768=LINE('',#767,#766);
#769=EDGE_CURVE('E521',#762,#99,#768,.T.);
#770=ORIENTED_EDGE('',*,*,#769,.T.);
#771=ORIENTED_EDGE('',*,*,#100,.T.);
#772=DIRECTION('',(-0.95105651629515,0.,0.309016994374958));
#773=VECTOR('',#772,1.);
#774=CARTESIAN_POINT('',(-3.31019610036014,0.,0.621526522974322));
#775=LINE('',#774,#773);
#776=CARTESIAN_POINT('',(-3.31019610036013,0.,0.621526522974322));
#777=VERTEX_POINT('',#776);
#778=EDGE_CURVE('E554',#93,#777,#775,.T.);
#779=ORIENTED_EDGE('',*,*,#778,.T.);
#780=CARTESIAN_POINT('',(0.,0.,0.));
#781=DIRECTION('',(0.,1.,0.));
#782=DIRECTION('',(-0.95105651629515,0.,0.309016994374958));
#783=AXIS2_PLACEMENT_3D('',#780,#781,#782);
#784=CIRCLE('',#783,3.36804);
#785=CARTESIAN_POINT('',(-3.04332902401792,0.,1.44285893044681));
#786=VERTEX_POINT('',#785);
#787=EDGE_CURVE('E63',#777,#786,#784,.T.);
#788=ORIENTED_EDGE('',*,*,#787,.T.);
#789=DIRECTION('',(0.95105651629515,0.,-0.309016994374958));
#790=VECTOR('',#789,1.);
#791=CARTESIAN_POINT('',(-3.04332902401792,0.,1.44285893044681));
#792=LINE('',#791,#790);
#793=EDGE_CURVE('E321',#786,#72,#792,.T.);
#794=ORIENTED_EDGE('',*,*,#793,.T.);
#795=ORIENTED_EDGE('',*,*,#73,.T.);
#796=DIRECTION('',(-0.587785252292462,0.,0.809016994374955));
#797=VECTOR('',#796,1.);
#798=CARTESIAN_POINT('',(-2.3126807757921,0.,2.44850996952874));
#799=LINE('',#798,#797);
#800=EDGE_CURVE('E300',#66,#563,#799,.T.);
#801=ORIENTED_EDGE('',*,*,#800,.T.);
#802=EDGE_LOOP('',(#567,#573,#574,#582,#591,#599,#603,#611,#620,#626,#627,#635,#644,#650,#651,
#659,#668,#674,#675,#683,#692,#698,#699,#707,#716,#722,#723,#731,#740,#746,#747,#755,#764,#770,
#771,#779,#788,#794,#795,#801));
#803=FACE_BOUND('',#802,.T.);
#804=ADVANCED_FACE('F316',(#556,#803),#545,.F.);
#805=CARTESIAN_POINT('',(0.,0.6096,0.));
#806=DIRECTION('',(0.,-1.,0.));
#807=DIRECTION('',(0.,0.,-1.));
#808=AXIS2_PLACEMENT_3D('',#805,#806,#807);
#809=CYLINDRICAL_SURFACE('',#808,4.8387);
#810=ORIENTED_EDGE('',*,*,#536,.F.);
#811=EDGE_LOOP('',(#810));
#812=FACE_BOUND('',#811,.T.);
#813=ORIENTED_EDGE('',*,*,#553,.T.);
#814=EDGE_LOOP('',(#813));
#815=FACE_BOUND('',#814,.T.);
#816=ADVANCED_FACE('F43',(#812,#815),#809,.T.);
#817=DIRECTION('',(0.,1.,0.));
#818=VECTOR('',#817,1.);
#819=CARTESIAN_POINT('',(1.1522010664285,0.,2.32049075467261));
#820=LINE('',#819,#818);
#821=EDGE_CURVE('E364',#601,#496,#820,.T.);
#822=ORIENTED_EDGE('',*,*,#821,.F.);
#823=ORIENTED_EDGE('',*,*,#602,.F.);
#824=DIRECTION('',(0.,1.,0.));
#825=VECTOR('',#824,1.);
#826=CARTESIAN_POINT('',(0.4318,0.,2.55456325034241));
#827=LINE('',#826,#825);
#828=EDGE_CURVE('E330',#597,#500,#827,.T.);
#829=ORIENTED_EDGE('',*,*,#828,.T.);
#830=ORIENTED_EDGE('',*,*,#501,.T.);
#831=EDGE_LOOP('',(#822,#823,#829,#830));
#832=FACE_BOUND('',#831,.T.);
#833=ADVANCED_FACE('F604',(#832),#23,.F.);
#834=CARTESIAN_POINT('',(0.4318,0.,3.34024582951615));
#835=DIRECTION('',(1.,0.,0.));
#836=DIRECTION('',(0.,0.,-1.));
#837=AXIS2_PLACEMENT_3D('',#834,#835,#836);
#838=PLANE('',#837);
#839=ORIENTED_EDGE('',*,*,#509,.T.);
#840=ORIENTED_EDGE('',*,*,#828,.F.);
#841=ORIENTED_EDGE('',*,*,#598,.F.);
#842=DIRECTION('',(0.,1.,0.));
#843=VECTOR('',#842,1.);
#844=CARTESIAN_POINT('',(0.4318,0.,3.34024582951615));
#845=LINE('',#844,#843);
#846=EDGE_CURVE('E342',#589,#508,#845,.T.);
#847=ORIENTED_EDGE('',*,*,#846,.T.);
#848=EDGE_LOOP('',(#839,#840,#841,#847));
#849=FACE_BOUND('',#848,.T.);
#850=ADVANCED_FACE('F767',(#849),#838,.F.);
#851=CARTESIAN_POINT('',(0.,0.,0.));
#852=DIRECTION('',(0.,1.,0.));
#853=DIRECTION('',(0.,0.,1.));
#854=AXIS2_PLACEMENT_3D('',#851,#852,#853);
#855=CYLINDRICAL_SURFACE('',#854,3.36804);
#856=ORIENTED_EDGE('',*,*,#518,.T.);
#857=ORIENTED_EDGE('',*,*,#846,.F.);
#858=ORIENTED_EDGE('',*,*,#590,.F.);
#859=DIRECTION('',(0.,1.,0.));
#860=VECTOR('',#859,1.);
#861=CARTESIAN_POINT('',(-0.431799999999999,0.,3.34024582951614));
#862=LINE('',#861,#860);
#863=EDGE_CURVE('E338',#580,#517,#862,.T.);
#864=ORIENTED_EDGE('',*,*,#863,.T.);
#865=EDGE_LOOP('',(#856,#857,#858,#864));
#866=FACE_BOUND('',#865,.T.);
#867=ADVANCED_FACE('F596',(#866),#855,.F.);
#868=CARTESIAN_POINT('',(-0.4318,0.,3.34024582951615));
#869=DIRECTION('',(-1.,0.,0.));
#870=DIRECTION('',(0.,0.,1.));
#871=AXIS2_PLACEMENT_3D('',#868,#869,#870);
#872=PLANE('',#871);
#873=ORIENTED_EDGE('',*,*,#524,.T.);
#874=ORIENTED_EDGE('',*,*,#863,.F.);
#875=ORIENTED_EDGE('',*,*,#581,.F.);
#876=ORIENTED_EDGE('',*,*,#49,.T.);
#877=EDGE_LOOP('',(#873,#874,#875,#876));
#878=FACE_BOUND('',#877,.T.);
#879=ADVANCED_FACE('F587',(#878),#872,.F.);
#880=CARTESIAN_POINT('',(2.31268077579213,0.,2.44850996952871));
#881=DIRECTION('',(0.809016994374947,0.,-0.587785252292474));
#882=DIRECTION('',(-0.587785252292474,0.,-0.809016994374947));
#883=AXIS2_PLACEMENT_3D('',#880,#881,#882);
#884=PLANE('',#883);
#885=ORIENTED_EDGE('',*,*,#480,.T.);
#886=ORIENTED_EDGE('',*,*,#270,.F.);
#887=ORIENTED_EDGE('',*,*,#625,.F.);
#888=DIRECTION('',(0.,1.,0.));
#889=VECTOR('',#888,1.);
#890=CARTESIAN_POINT('',(2.31268077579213,0.,2.44850996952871));
#891=LINE('',#890,#889);
#892=EDGE_CURVE('E367',#618,#479,#891,.T.);
#893=ORIENTED_EDGE('',*,*,#892,.T.);
#894=EDGE_LOOP('',(#885,#886,#887,#893));
#895=FACE_BOUND('',#894,.T.);
#896=ADVANCED_FACE('F818',(#895),#884,.F.);
#897=CARTESIAN_POINT('',(0.,0.,0.));
#898=DIRECTION('',(0.,1.,0.));
#899=DIRECTION('',(0.,0.,1.));
#900=AXIS2_PLACEMENT_3D('',#897,#898,#899);
#901=CYLINDRICAL_SURFACE('',#900,3.36804);
#902=ORIENTED_EDGE('',*,*,#489,.T.);
#903=ORIENTED_EDGE('',*,*,#892,.F.);
#904=ORIENTED_EDGE('',*,*,#619,.F.);
#905=DIRECTION('',(0.,1.,0.));
#906=VECTOR('',#905,1.);
#907=CARTESIAN_POINT('',(1.61401369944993,0.,2.95612131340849));
#908=LINE('',#907,#906);
#909=EDGE_CURVE('E366',#609,#488,#908,.T.);
#910=ORIENTED_EDGE('',*,*,#909,.T.);
#911=EDGE_LOOP('',(#902,#903,#904,#910));
#912=FACE_BOUND('',#911,.T.);
#913=ADVANCED_FACE('F614',(#912),#901,.F.);
#914=CARTESIAN_POINT('',(1.61401369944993,0.,2.95612131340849));
#915=DIRECTION('',(-0.809016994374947,0.,0.587785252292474));
#916=DIRECTION('',(0.587785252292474,0.,0.809016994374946));
#917=AXIS2_PLACEMENT_3D('',#914,#915,#916);
#918=PLANE('',#917);
#919=ORIENTED_EDGE('',*,*,#497,.T.);
#920=ORIENTED_EDGE('',*,*,#909,.F.);
#921=ORIENTED_EDGE('',*,*,#610,.F.);
#922=ORIENTED_EDGE('',*,*,#821,.T.);
#923=EDGE_LOOP('',(#919,#920,#921,#922));
#924=FACE_BOUND('',#923,.T.);
#925=ADVANCED_FACE('F606',(#924),#918,.F.);
#926=CARTESIAN_POINT('',(3.31019610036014,0.,0.621526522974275));
#927=DIRECTION('',(0.309016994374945,0.,-0.951056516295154));
#928=DIRECTION('',(-0.951056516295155,0.,-0.309016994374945));
#929=AXIS2_PLACEMENT_3D('',#926,#927,#928);
#930=PLANE('',#929);
#931=ORIENTED_EDGE('',*,*,#456,.T.);
#932=ORIENTED_EDGE('',*,*,#243,.F.);
#933=ORIENTED_EDGE('',*,*,#649,.F.);
#934=DIRECTION('',(0.,1.,0.));
#935=VECTOR('',#934,1.);
#936=CARTESIAN_POINT('',(3.31019610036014,0.,0.621526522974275));
#937=LINE('',#936,#935);
#938=EDGE_CURVE('E394',#642,#455,#937,.T.);
#939=ORIENTED_EDGE('',*,*,#938,.T.);
#940=EDGE_LOOP('',(#931,#932,#933,#939));
#941=FACE_BOUND('',#940,.T.);
#942=ADVANCED_FACE('F701',(#941),#930,.F.);
#943=CARTESIAN_POINT('',(0.,0.,0.));
#944=DIRECTION('',(0.,1.,0.));
#945=DIRECTION('',(0.,0.,1.));
#946=AXIS2_PLACEMENT_3D('',#943,#944,#945);
#947=CYLINDRICAL_SURFACE('',#946,3.36804);
#948=ORIENTED_EDGE('',*,*,#465,.T.);
#949=ORIENTED_EDGE('',*,*,#938,.F.);
#950=ORIENTED_EDGE('',*,*,#643,.F.);
#951=DIRECTION('',(0.,1.,0.));
#952=VECTOR('',#951,1.);
#953=CARTESIAN_POINT('',(3.04332902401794,0.,1.44285893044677));
#954=LINE('',#953,#952);
#955=EDGE_CURVE('E395',#633,#464,#954,.T.);
#956=ORIENTED_EDGE('',*,*,#955,.T.);
#957=EDGE_LOOP('',(#948,#949,#950,#956));
#958=FACE_BOUND('',#957,.T.);
#959=ADVANCED_FACE('F697',(#958),#947,.F.);
#960=CARTESIAN_POINT('',(3.04332902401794,0.,1.44285893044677));
#961=DIRECTION('',(-0.309016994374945,0.,0.951056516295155));
#962=DIRECTION('',(0.951056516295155,0.,0.309016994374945));
#963=AXIS2_PLACEMENT_3D('',#960,#961,#962);
#964=PLANE('',#963);
#965=ORIENTED_EDGE('',*,*,#471,.T.);
#966=ORIENTED_EDGE('',*,*,#955,.F.);
#967=ORIENTED_EDGE('',*,*,#634,.F.);
#968=ORIENTED_EDGE('',*,*,#258,.T.);
#969=EDGE_LOOP('',(#965,#966,#967,#968));
#970=FACE_BOUND('',#969,.T.);
#971=ADVANCED_FACE('F696',(#970),#964,.F.);
#972=CARTESIAN_POINT('',(3.04332902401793,0.,-1.44285893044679));
#973=DIRECTION('',(-0.309016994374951,0.,-0.951056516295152));
#974=DIRECTION('',(-0.951056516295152,0.,0.309016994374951));
#975=AXIS2_PLACEMENT_3D('',#972,#973,#974);
#976=PLANE('',#975);
#977=ORIENTED_EDGE('',*,*,#432,.T.);
#978=ORIENTED_EDGE('',*,*,#216,.F.);
#979=ORIENTED_EDGE('',*,*,#673,.F.);
#980=DIRECTION('',(0.,1.,0.));
#981=VECTOR('',#980,1.);
#982=CARTESIAN_POINT('',(3.04332902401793,0.,-1.44285893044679));
#983=LINE('',#982,#981);
#984=EDGE_CURVE('E423',#666,#431,#983,.T.);
#985=ORIENTED_EDGE('',*,*,#984,.T.);
#986=EDGE_LOOP('',(#977,#978,#979,#985));
#987=FACE_BOUND('',#986,.T.);
#988=ADVANCED_FACE('F712',(#987),#976,.F.);
#989=CARTESIAN_POINT('',(0.,0.,0.));
#990=DIRECTION('',(0.,1.,0.));
#991=DIRECTION('',(0.,0.,1.));
#992=AXIS2_PLACEMENT_3D('',#989,#990,#991);
#993=CYLINDRICAL_SURFACE('',#992,3.36804);
#994=ORIENTED_EDGE('',*,*,#441,.T.);
#995=ORIENTED_EDGE('',*,*,#984,.F.);
#996=ORIENTED_EDGE('',*,*,#667,.F.);
#997=DIRECTION('',(0.,1.,0.));
#998=VECTOR('',#997,1.);
#999=CARTESIAN_POINT('',(3.31019610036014,0.,-0.6215265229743));
#1000=LINE('',#999,#998);
#1001=EDGE_CURVE('E419',#657,#440,#1000,.T.);
#1002=ORIENTED_EDGE('',*,*,#1001,.T.);
#1003=EDGE_LOOP('',(#994,#995,#996,#1002));
#1004=FACE_BOUND('',#1003,.T.);
#1005=ADVANCED_FACE('F711',(#1004),#993,.F.);
#1006=CARTESIAN_POINT('',(3.31019610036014,0.,-0.6215265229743));
#1007=DIRECTION('',(0.309016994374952,0.,0.951056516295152));
#1008=DIRECTION('',(0.951056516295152,0.,-0.309016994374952));
#1009=AXIS2_PLACEMENT_3D('',#1006,#1007,#1008);
#1010=PLANE('',#1009);
#1011=ORIENTED_EDGE('',*,*,#447,.T.);
#1012=ORIENTED_EDGE('',*,*,#1001,.F.);
#1013=ORIENTED_EDGE('',*,*,#658,.F.);
#1014=ORIENTED_EDGE('',*,*,#231,.T.);
#1015=EDGE_LOOP('',(#1011,#1012,#1013,#1014));
#1016=FACE_BOUND('',#1015,.T.);
#1017=ADVANCED_FACE('F709',(#1016),#1010,.F.);
#1018=CARTESIAN_POINT('',(1.61401369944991,0.,-2.9561213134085));
#1019=DIRECTION('',(-0.809016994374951,0.,-0.587785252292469));
#1020=DIRECTION('',(-0.587785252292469,0.,0.809016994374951));
#1021=AXIS2_PLACEMENT_3D('',#1018,#1019,#1020);
#1022=PLANE('',#1021);
#1023=ORIENTED_EDGE('',*,*,#408,.T.);
#1024=ORIENTED_EDGE('',*,*,#189,.F.);
#1025=ORIENTED_EDGE('',*,*,#697,.F.);
#1026=DIRECTION('',(0.,1.,0.));
#1027=VECTOR('',#1026,1.);
#1028=CARTESIAN_POINT('',(1.61401369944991,0.,-2.9561213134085));
#1029=LINE('',#1028,#1027);
#1030=EDGE_CURVE('E450',#690,#407,#1029,.T.);
#1031=ORIENTED_EDGE('',*,*,#1030,.T.);
#1032=EDGE_LOOP('',(#1023,#1024,#1025,#1031));
#1033=FACE_BOUND('',#1032,.T.);
#1034=ADVANCED_FACE('F723',(#1033),#1022,.F.);
#1035=CARTESIAN_POINT('',(0.,0.,0.));
#1036=DIRECTION('',(0.,1.,0.));
#1037=DIRECTION('',(0.,0.,1.));
#1038=AXIS2_PLACEMENT_3D('',#1035,#1036,#1037);
#1039=CYLINDRICAL_SURFACE('',#1038,3.36804);
#1040=ORIENTED_EDGE('',*,*,#417,.T.);
#1041=ORIENTED_EDGE('',*,*,#1030,.F.);
#1042=ORIENTED_EDGE('',*,*,#691,.F.);
#1043=DIRECTION('',(0.,1.,0.));
#1044=VECTOR('',#1043,1.);
#1045=CARTESIAN_POINT('',(2.31268077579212,0.,-2.44850996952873));
#1046=LINE('',#1045,#1044);
#1047=EDGE_CURVE('E443',#681,#416,#1046,.T.);
#1048=ORIENTED_EDGE('',*,*,#1047,.T.);
#1049=EDGE_LOOP('',(#1040,#1041,#1042,#1048));
#1050=FACE_BOUND('',#1049,.T.);
#1051=ADVANCED_FACE('F724',(#1050),#1039,.F.);
#1052=CARTESIAN_POINT('',(2.31268077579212,0.,-2.44850996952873));
#1053=DIRECTION('',(0.809016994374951,0.,0.587785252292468));
#1054=DIRECTION('',(0.587785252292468,0.,-0.809016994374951));
#1055=AXIS2_PLACEMENT_3D('',#1052,#1053,#1054);
#1056=PLANE('',#1055);
#1057=ORIENTED_EDGE('',*,*,#423,.T.);
#1058=ORIENTED_EDGE('',*,*,#1047,.F.);
#1059=ORIENTED_EDGE('',*,*,#682,.F.);
#1060=ORIENTED_EDGE('',*,*,#204,.T.);
#1061=EDGE_LOOP('',(#1057,#1058,#1059,#1060));
#1062=FACE_BOUND('',#1061,.T.);
#1063=ADVANCED_FACE('F719',(#1062),#1056,.F.);
#1064=CARTESIAN_POINT('',(-0.431800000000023,0.,-3.34024582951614));
#1065=DIRECTION('',(-1.,0.,0.));
#1066=DIRECTION('',(0.,0.,1.));
#1067=AXIS2_PLACEMENT_3D('',#1064,#1065,#1066);
#1068=PLANE('',#1067);
#1069=ORIENTED_EDGE('',*,*,#384,.T.);
#1070=ORIENTED_EDGE('',*,*,#162,.F.);
#1071=ORIENTED_EDGE('',*,*,#721,.F.);
#1072=DIRECTION('',(0.,1.,0.));
#1073=VECTOR('',#1072,1.);
#1074=CARTESIAN_POINT('',(-0.431800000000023,0.,-3.34024582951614));
#1075=LINE('',#1074,#1073);
#1076=EDGE_CURVE('E472',#714,#383,#1075,.T.);
#1077=ORIENTED_EDGE('',*,*,#1076,.T.);
#1078=EDGE_LOOP('',(#1069,#1070,#1071,#1077));
#1079=FACE_BOUND('',#1078,.T.);
#1080=ADVANCED_FACE('F740',(#1079),#1068,.F.);
#1081=CARTESIAN_POINT('',(0.,0.,0.));
#1082=DIRECTION('',(0.,1.,0.));
#1083=DIRECTION('',(0.,0.,1.));
#1084=AXIS2_PLACEMENT_3D('',#1081,#1082,#1083);
#1085=CYLINDRICAL_SURFACE('',#1084,3.36804);
#1086=ORIENTED_EDGE('',*,*,#393,.T.);
#1087=ORIENTED_EDGE('',*,*,#1076,.F.);
#1088=ORIENTED_EDGE('',*,*,#715,.F.);
#1089=DIRECTION('',(0.,1.,0.));
#1090=VECTOR('',#1089,1.);
#1091=CARTESIAN_POINT('',(0.431799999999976,0.,-3.34024582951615));
#1092=LINE('',#1091,#1090);
#1093=EDGE_CURVE('E468',#705,#392,#1092,.T.);
#1094=ORIENTED_EDGE('',*,*,#1093,.T.);
#1095=EDGE_LOOP('',(#1086,#1087,#1088,#1094));
#1096=FACE_BOUND('',#1095,.T.);
#1097=ADVANCED_FACE('F734',(#1096),#1085,.F.);
#1098=CARTESIAN_POINT('',(0.431799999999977,0.,-3.34024582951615));
#1099=DIRECTION('',(1.,0.,0.));
#1100=DIRECTION('',(0.,0.,-1.));
#1101=AXIS2_PLACEMENT_3D('',#1098,#1099,#1100);
#1102=PLANE('',#1101);
#1103=ORIENTED_EDGE('',*,*,#399,.T.);
#1104=ORIENTED_EDGE('',*,*,#1093,.F.);
#1105=ORIENTED_EDGE('',*,*,#706,.F.);
#1106=ORIENTED_EDGE('',*,*,#177,.T.);
#1107=EDGE_LOOP('',(#1103,#1104,#1105,#1106));
#1108=FACE_BOUND('',#1107,.T.);
#1109=ADVANCED_FACE('F735',(#1108),#1102,.F.);
#1110=CARTESIAN_POINT('',(-2.31268077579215,0.,-2.44850996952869));
#1111=DIRECTION('',(-0.809016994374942,0.,0.58778525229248));
#1112=DIRECTION('',(0.58778525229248,0.,0.809016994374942));
#1113=AXIS2_PLACEMENT_3D('',#1110,#1111,#1112);
#1114=PLANE('',#1113);
#1115=ORIENTED_EDGE('',*,*,#360,.T.);
#1116=ORIENTED_EDGE('',*,*,#135,.F.);
#1117=ORIENTED_EDGE('',*,*,#745,.F.);
#1118=DIRECTION('',(0.,1.,0.));
#1119=VECTOR('',#1118,1.);
#1120=CARTESIAN_POINT('',(-2.31268077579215,0.,-2.44850996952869));
#1121=LINE('',#1120,#1119);
#1122=EDGE_CURVE('E497',#738,#359,#1121,.T.);
#1123=ORIENTED_EDGE('',*,*,#1122,.T.);
#1124=EDGE_LOOP('',(#1115,#1116,#1117,#1123));
#1125=FACE_BOUND('',#1124,.T.);
#1126=ADVANCED_FACE('F747',(#1125),#1114,.F.);
#1127=CARTESIAN_POINT('',(0.,0.,0.));
#1128=DIRECTION('',(0.,1.,0.));
#1129=DIRECTION('',(0.,0.,1.));
#1130=AXIS2_PLACEMENT_3D('',#1127,#1128,#1129);
#1131=CYLINDRICAL_SURFACE('',#1130,3.36804);
#1132=ORIENTED_EDGE('',*,*,#369,.T.);
#1133=ORIENTED_EDGE('',*,*,#1122,.F.);
#1134=ORIENTED_EDGE('',*,*,#739,.F.);
#1135=DIRECTION('',(0.,1.,0.));
#1136=VECTOR('',#1135,1.);
#1137=CARTESIAN_POINT('',(-1.61401369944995,0.,-2.95612131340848));
#1138=LINE('',#1137,#1136);
#1139=EDGE_CURVE('E496',#729,#368,#1138,.T.);
#1140=ORIENTED_EDGE('',*,*,#1139,.T.);
#1141=EDGE_LOOP('',(#1132,#1133,#1134,#1140));
#1142=FACE_BOUND('',#1141,.T.);
#1143=ADVANCED_FACE('F743',(#1142),#1131,.F.);
#1144=CARTESIAN_POINT('',(-1.61401369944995,0.,-2.95612131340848));
#1145=DIRECTION('',(0.809016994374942,0.,-0.58778525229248));
#1146=DIRECTION('',(-0.58778525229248,0.,-0.809016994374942));
#1147=AXIS2_PLACEMENT_3D('',#1144,#1145,#1146);
#1148=PLANE('',#1147);
#1149=ORIENTED_EDGE('',*,*,#375,.T.);
#1150=ORIENTED_EDGE('',*,*,#1139,.F.);
#1151=ORIENTED_EDGE('',*,*,#730,.F.);
#1152=ORIENTED_EDGE('',*,*,#150,.T.);
#1153=EDGE_LOOP('',(#1149,#1150,#1151,#1152));
#1154=FACE_BOUND('',#1153,.T.);
#1155=ADVANCED_FACE('F744',(#1154),#1148,.F.);
#1156=CARTESIAN_POINT('',(-3.31019610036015,0.,-0.621526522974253));
#1157=DIRECTION('',(-0.309016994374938,0.,0.951056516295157));
#1158=DIRECTION('',(0.951056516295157,0.,0.309016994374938));
#1159=AXIS2_PLACEMENT_3D('',#1156,#1157,#1158);
#1160=PLANE('',#1159);
#1161=ORIENTED_EDGE('',*,*,#336,.T.);
#1162=ORIENTED_EDGE('',*,*,#108,.F.);
#1163=ORIENTED_EDGE('',*,*,#769,.F.);
#1164=DIRECTION('',(0.,1.,0.));
#1165=VECTOR('',#1164,1.);
#1166=CARTESIAN_POINT('',(-3.31019610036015,0.,-0.621526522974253));
#1167=LINE('',#1166,#1165);
#1168=EDGE_CURVE('E524',#762,#335,#1167,.T.);
#1169=ORIENTED_EDGE('',*,*,#1168,.T.);
#1170=EDGE_LOOP('',(#1161,#1162,#1163,#1169));
#1171=FACE_BOUND('',#1170,.T.);
#1172=ADVANCED_FACE('F967',(#1171),#1160,.F.);
#1173=CARTESIAN_POINT('',(0.,0.,0.));
#1174=DIRECTION('',(0.,1.,0.));
#1175=DIRECTION('',(0.,0.,1.));
#1176=AXIS2_PLACEMENT_3D('',#1173,#1174,#1175);
#1177=CYLINDRICAL_SURFACE('',#1176,3.36804);
#1178=ORIENTED_EDGE('',*,*,#345,.T.);
#1179=ORIENTED_EDGE('',*,*,#1168,.F.);
#1180=ORIENTED_EDGE('',*,*,#763,.F.);
#1181=DIRECTION('',(0.,1.,0.));
#1182=VECTOR('',#1181,1.);
#1183=CARTESIAN_POINT('',(-3.04332902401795,0.,-1.44285893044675));
#1184=LINE('',#1183,#1182);
#1185=EDGE_CURVE('E525',#753,#344,#1184,.T.);
#1186=ORIENTED_EDGE('',*,*,#1185,.T.);
#1187=EDGE_LOOP('',(#1178,#1179,#1180,#1186));
#1188=FACE_BOUND('',#1187,.T.);
#1189=ADVANCED_FACE('F651',(#1188),#1177,.F.);
#1190=CARTESIAN_POINT('',(-3.04332902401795,0.,-1.44285893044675));
#1191=DIRECTION('',(0.309016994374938,0.,-0.951056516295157));
#1192=DIRECTION('',(-0.951056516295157,0.,-0.309016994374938));
#1193=AXIS2_PLACEMENT_3D('',#1190,#1191,#1192);
#1194=PLANE('',#1193);
#1195=ORIENTED_EDGE('',*,*,#351,.T.);
#1196=ORIENTED_EDGE('',*,*,#1185,.F.);
#1197=ORIENTED_EDGE('',*,*,#754,.F.);
#1198=ORIENTED_EDGE('',*,*,#123,.T.);
#1199=EDGE_LOOP('',(#1195,#1196,#1197,#1198));
#1200=FACE_BOUND('',#1199,.T.);
#1201=ADVANCED_FACE('F646',(#1200),#1194,.F.);
#1202=CARTESIAN_POINT('',(-3.04332902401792,0.,1.44285893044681));
#1203=DIRECTION('',(0.309016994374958,0.,0.95105651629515));
#1204=DIRECTION('',(0.95105651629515,0.,-0.309016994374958));
#1205=AXIS2_PLACEMENT_3D('',#1202,#1203,#1204);
#1206=PLANE('',#1205);
#1207=ORIENTED_EDGE('',*,*,#312,.T.);
#1208=ORIENTED_EDGE('',*,*,#81,.F.);
#1209=ORIENTED_EDGE('',*,*,#793,.F.);
#1210=DIRECTION('',(0.,1.,0.));
#1211=VECTOR('',#1210,1.);
#1212=CARTESIAN_POINT('',(-3.04332902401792,0.,1.44285893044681));
#1213=LINE('',#1212,#1211);
#1214=EDGE_CURVE('E548',#786,#311,#1213,.T.);
#1215=ORIENTED_EDGE('',*,*,#1214,.T.);
#1216=EDGE_LOOP('',(#1207,#1208,#1209,#1215));
#1217=FACE_BOUND('',#1216,.T.);
#1218=ADVANCED_FACE('F668',(#1217),#1206,.F.);
#1219=CARTESIAN_POINT('',(0.,0.,0.));
#1220=DIRECTION('',(0.,1.,0.));
#1221=DIRECTION('',(0.,0.,1.));
#1222=AXIS2_PLACEMENT_3D('',#1219,#1220,#1221);
#1223=CYLINDRICAL_SURFACE('',#1222,3.36804);
#1224=ORIENTED_EDGE('',*,*,#321,.T.);
#1225=ORIENTED_EDGE('',*,*,#1214,.F.);
#1226=ORIENTED_EDGE('',*,*,#787,.F.);
#1227=DIRECTION('',(0.,1.,0.));
#1228=VECTOR('',#1227,1.);
#1229=CARTESIAN_POINT('',(-3.31019610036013,0.,0.621526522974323));
#1230=LINE('',#1229,#1228);
#1231=EDGE_CURVE('E549',#777,#320,#1230,.T.);
#1232=ORIENTED_EDGE('',*,*,#1231,.T.);
#1233=EDGE_LOOP('',(#1224,#1225,#1226,#1232));
#1234=FACE_BOUND('',#1233,.T.);
#1235=ADVANCED_FACE('F670',(#1234),#1223,.F.);
#1236=CARTESIAN_POINT('',(-3.31019610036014,0.,0.621526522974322));
#1237=DIRECTION('',(-0.309016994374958,0.,-0.95105651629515));
#1238=DIRECTION('',(-0.95105651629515,0.,0.309016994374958));
#1239=AXIS2_PLACEMENT_3D('',#1236,#1237,#1238);
#1240=PLANE('',#1239);
#1241=ORIENTED_EDGE('',*,*,#327,.T.);
#1242=ORIENTED_EDGE('',*,*,#1231,.F.);
#1243=ORIENTED_EDGE('',*,*,#778,.F.);
#1244=ORIENTED_EDGE('',*,*,#96,.T.);
#1245=EDGE_LOOP('',(#1241,#1242,#1243,#1244));
#1246=FACE_BOUND('',#1245,.T.);
#1247=ADVANCED_FACE('F664',(#1246),#1240,.F.);
#1248=CARTESIAN_POINT('',(-1.61401369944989,0.,2.95612131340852));
#1249=DIRECTION('',(0.809016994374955,0.,0.587785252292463));
#1250=DIRECTION('',(0.587785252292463,0.,-0.809016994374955));
#1251=AXIS2_PLACEMENT_3D('',#1248,#1249,#1250);
#1252=PLANE('',#1251);
#1253=ORIENTED_EDGE('',*,*,#288,.T.);
#1254=ORIENTED_EDGE('',*,*,#32,.F.);
#1255=ORIENTED_EDGE('',*,*,#572,.F.);
#1256=DIRECTION('',(0.,1.,0.));
#1257=VECTOR('',#1256,1.);
#1258=CARTESIAN_POINT('',(-1.61401369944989,0.,2.95612131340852));
#1259=LINE('',#1258,#1257);
#1260=EDGE_CURVE('E568',#565,#287,#1259,.T.);
#1261=ORIENTED_EDGE('',*,*,#1260,.T.);
#1262=EDGE_LOOP('',(#1253,#1254,#1255,#1261));
#1263=FACE_BOUND('',#1262,.T.);
#1264=ADVANCED_FACE('F1017',(#1263),#1252,.F.);
#1265=CARTESIAN_POINT('',(0.,0.,0.));
#1266=DIRECTION('',(0.,1.,0.));
#1267=DIRECTION('',(0.,0.,1.));
#1268=AXIS2_PLACEMENT_3D('',#1265,#1266,#1267);
#1269=CYLINDRICAL_SURFACE('',#1268,3.36804);
#1270=ORIENTED_EDGE('',*,*,#297,.T.);
#1271=ORIENTED_EDGE('',*,*,#1260,.F.);
#1272=ORIENTED_EDGE('',*,*,#566,.F.);
#1273=DIRECTION('',(0.,1.,0.));
#1274=VECTOR('',#1273,1.);
#1275=CARTESIAN_POINT('',(-2.3126807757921,0.,2.44850996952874));
#1276=LINE('',#1275,#1274);
#1277=EDGE_CURVE('E303',#563,#296,#1276,.T.);
#1278=ORIENTED_EDGE('',*,*,#1277,.T.);
#1279=EDGE_LOOP('',(#1270,#1271,#1272,#1278));
#1280=FACE_BOUND('',#1279,.T.);
#1281=ADVANCED_FACE('F1028',(#1280),#1269,.F.);
#1282=CARTESIAN_POINT('',(-2.3126807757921,0.,2.44850996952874));
#1283=DIRECTION('',(-0.809016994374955,0.,-0.587785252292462));
#1284=DIRECTION('',(-0.587785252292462,0.,0.809016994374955));
#1285=AXIS2_PLACEMENT_3D('',#1282,#1283,#1284);
#1286=PLANE('',#1285);
#1287=ORIENTED_EDGE('',*,*,#303,.T.);
#1288=ORIENTED_EDGE('',*,*,#1277,.F.);
#1289=ORIENTED_EDGE('',*,*,#800,.F.);
#1290=ORIENTED_EDGE('',*,*,#69,.T.);
#1291=EDGE_LOOP('',(#1287,#1288,#1289,#1290));
#1292=FACE_BOUND('',#1291,.T.);
#1293=ADVANCED_FACE('F297',(#1292),#1286,.F.);
#1294=CLOSED_SHELL('',(#60,#87,#114,#141,#168,#195,#222,#249,#276,#540,#804,#816,#833,#850,#867,
#879,#896,#913,#925,#942,#959,#971,#988,#1005,#1017,#1034,#1051,#1063,#1080,#1097,#1109,#1126,
#1143,#1155,#1172,#1189,#1201,#1218,#1235,#1247,#1264,#1281,#1293));
#1295=MANIFOLD_SOLID_BREP('B2',#1294);
#1296=ADVANCED_BREP_SHAPE_REPRESENTATION('',(#18,#1295),#14);
#1297=SHAPE_DEFINITION_REPRESENTATION(#9,#1296);
ENDSEC;
END-ISO-10303-21;
